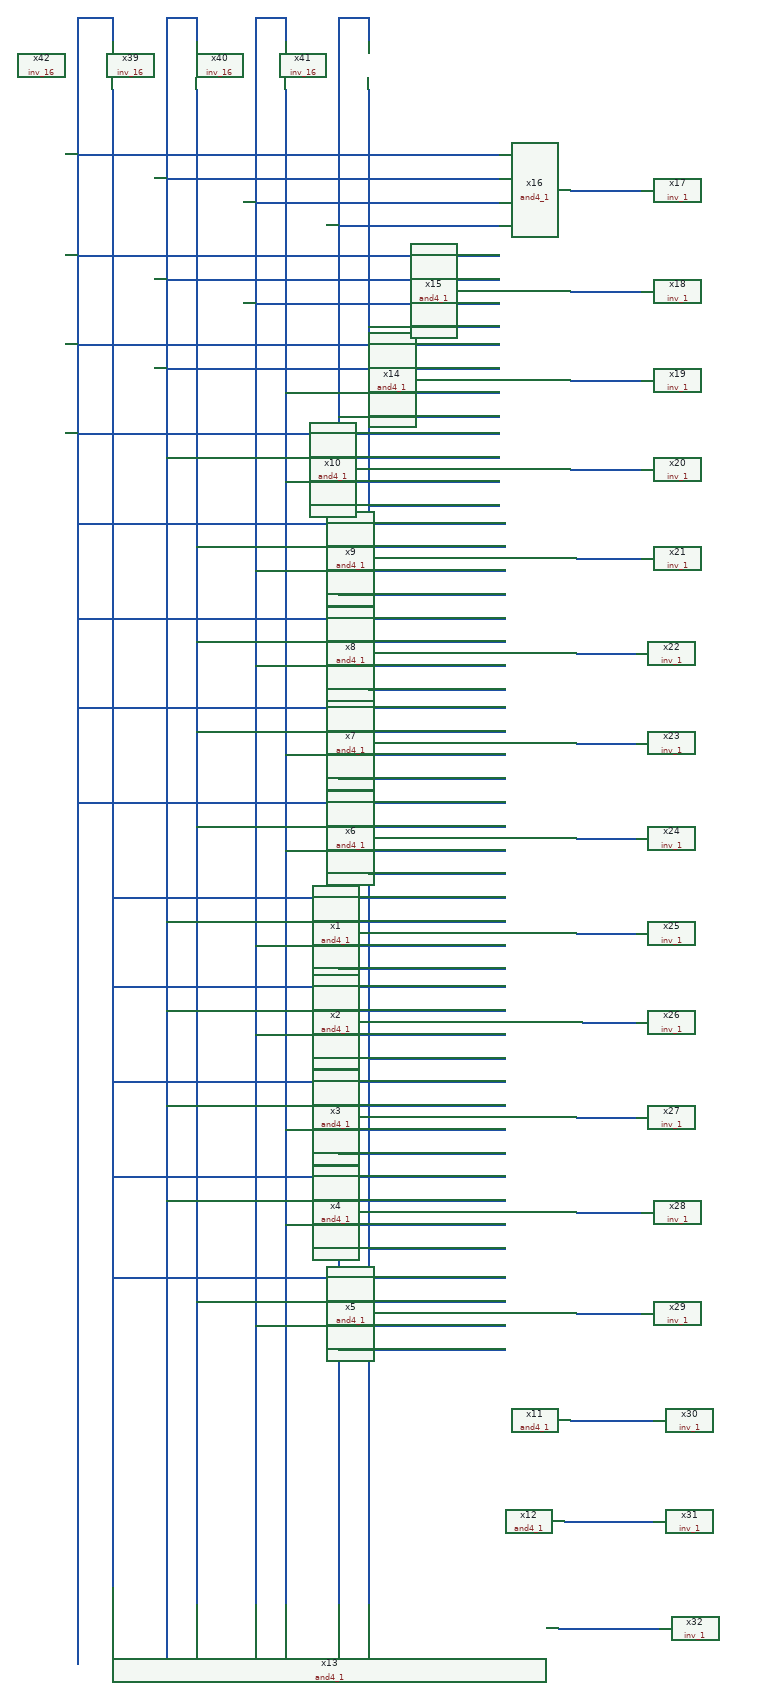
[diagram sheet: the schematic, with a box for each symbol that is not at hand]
v {xschem version=3.1.0 file_version=1.2
}
G {}
K {}
V {}
S {}
E {}
N 2040 -2550 2160 -2550 {
lab=#net1}
N 2040 -2380 2160 -2380 {
lab=#net2}
N 2040 -2230 2160 -2230 {
lab=#net3}
N 2040 -2080 2160 -2080 {
lab=#net4}
N 2050 -1930 2160 -1930 {
lab=#net5}
N 2050 -1770 2150 -1770 {
lab=#net6}
N 2050 -1620 2150 -1620 {
lab=#net7}
N 2050 -1460 2150 -1460 {
lab=#net8}
N 2050 -1300 2150 -1300 {
lab=#net9}
N 2060 -1150 2150 -1150 {
lab=#net10}
N 2050 -990 2150 -990 {
lab=#net11}
N 2050 -830 2160 -830 {
lab=#net12}
N 2050 -660 2160 -660 {
lab=#net13}
N 2040 -480 2180 -480 {
lab=#net14}
N 2030 -310 2180 -310 {
lab=#net15}
N 2020 -130 2190 -130 {
lab=#net16}
N 1270 -2840 1270 -2800 {
lab=#net17}
N 1210 -2840 1270 -2840 {
lab=#net17}
N 1410 -2840 1410 -2800 {
lab=#net18}
N 1360 -2840 1410 -2840 {
lab=#net18}
N 1560 -2840 1560 -2800 {
lab=#net19}
N 1510 -2840 1560 -2840 {
lab=#net19}
N 1700 -2840 1700 -2800 {
lab=#net20}
N 1650 -2840 1700 -2840 {
lab=#net20}
N 1210 -2610 1920 -2610 {
lab=#net17}
N 1210 -2840 1210 -2340 {
lab=#net17}
N 1210 -2340 1210 -1860 {
lab=#net17}
N 1210 -1860 1210 -1190 {
lab=#net17}
N 1210 -1190 1210 -70 {
lab=#net17}
N 1360 -2840 1360 -2390 {
lab=#net18}
N 1360 -2390 1360 -80 {
lab=#net18}
N 1510 -2840 1510 -2190 {
lab=#net19}
N 1650 -2840 1650 -2030 {
lab=#net20}
N 1270 -2720 1270 -2070 {
lab=#net27}
N 1410 -2720 1410 -2070 {
lab=#net28}
N 1560 -2720 1560 -2160 {
lab=#net29}
N 1700 -2720 1700 -2040 {
lab=#net30}
N 1360 -2570 1920 -2570 {
lab=#net18}
N 1510 -2530 1920 -2530 {
lab=#net19}
N 1650 -2490 1920 -2490 {
lab=#net20}
N 1210 -2440 1920 -2440 {
lab=#net17}
N 1360 -2400 1920 -2400 {
lab=#net18}
N 1510 -2360 1920 -2360 {
lab=#net19}
N 1700 -2320 1920 -2320 {
lab=#net30}
N 1210 -2290 1920 -2290 {
lab=#net17}
N 1360 -2250 1920 -2250 {
lab=#net18}
N 1510 -2190 1510 -2080 {
lab=#net19}
N 1270 -2070 1270 -1510 {
lab=#net27}
N 1410 -2070 1410 -1810 {
lab=#net28}
N 1510 -2080 1510 -1810 {
lab=#net19}
N 1560 -2160 1560 -1810 {
lab=#net29}
N 1650 -2030 1650 -1820 {
lab=#net20}
N 1700 -2040 1700 -1820 {
lab=#net30}
N 1650 -2170 1920 -2170 {
lab=#net20}
N 1560 -2210 1920 -2210 {
lab=#net29}
N 1210 -2140 1920 -2140 {
lab=#net17}
N 1360 -2100 1920 -2100 {
lab=#net18}
N 1560 -2060 1920 -2060 {
lab=#net29}
N 1700 -2020 1920 -2020 {
lab=#net30}
N 1210 -1990 1930 -1990 {
lab=#net17}
N 1410 -1950 1930 -1950 {
lab=#net28}
N 1510 -1910 1930 -1910 {
lab=#net19}
N 1650 -1870 1930 -1870 {
lab=#net20}
N 1410 -1810 1410 -1340 {
lab=#net28}
N 1510 -1810 1510 -1400 {
lab=#net19}
N 1560 -1810 1560 -1340 {
lab=#net29}
N 1650 -1820 1650 -1340 {
lab=#net20}
N 1700 -1820 1700 -1340 {
lab=#net30}
N 1210 -1830 1930 -1830 {
lab=#net17}
N 1410 -1790 1930 -1790 {
lab=#net28}
N 1510 -1750 1930 -1750 {
lab=#net19}
N 1700 -1710 1930 -1710 {
lab=#net30}
N 1210 -1680 1930 -1680 {
lab=#net17}
N 1410 -1640 1930 -1640 {
lab=#net28}
N 1560 -1600 1930 -1600 {
lab=#net29}
N 1650 -1560 1930 -1560 {
lab=#net20}
N 1210 -1520 1930 -1520 {
lab=#net17}
N 1410 -1480 1930 -1480 {
lab=#net28}
N 1560 -1440 1930 -1440 {
lab=#net29}
N 1700 -1400 1930 -1400 {
lab=#net30}
N 1270 -1510 1270 -990 {
lab=#net27}
N 1410 -1340 1410 -990 {
lab=#net28}
N 1510 -1400 1510 -990 {
lab=#net19}
N 1560 -1340 1560 -990 {
lab=#net29}
N 1650 -1340 1650 -980 {
lab=#net20}
N 1700 -1340 1700 -990 {
lab=#net30}
N 1270 -1360 1930 -1360 {
lab=#net27}
N 1360 -1320 1930 -1320 {
lab=#net18}
N 1510 -1280 1930 -1280 {
lab=#net19}
N 1650 -1240 1930 -1240 {}
N 1270 -1210 1930 -1210 {}
N 1360 -1170 1930 -1170 {}
N 1510 -1130 1930 -1130 {}
N 1700 -1090 1930 -1090 {}
N 1410 -990 1410 -580 {}
N 1270 -990 1270 -560 {}
N 1510 -990 1510 -560 {}
N 1560 -990 1560 -560 {}
N 1650 -980 1650 -570 {}
N 1700 -990 1700 -570 {}
N 1270 -1050 1930 -1050 {}
N 1270 -890 1930 -890 {}
N 1360 -1010 1930 -1010 {}
N 1560 -970 1930 -970 {}
N 1650 -930 1930 -930 {}
N 1700 -770 1930 -770 {}
N 1560 -810 1930 -810 {}
N 1360 -850 1930 -850 {}
N 1270 -720 1930 -720 {}
N 1410 -680 1930 -680 {}
N 1510 -640 1930 -640 {}
N 1650 -600 1930 -600 {}
N 1270 -560 1270 -200 {}
N 1410 -580 1410 -170 {}
N 1510 -560 1510 -170 {}
N 1560 -560 1560 -170 {}
N 1650 -570 1650 -170 {}
N 1700 -570 1700 -170 {}
C {sky130_stdcells/and4_1.sym} 1990 -1300 0 0 {name=x1 VGND=VGND VNB=VNB VPB=VPB VPWR=VPWR prefix=sky130_fd_sc_hd__ }
C {sky130_stdcells/and4_1.sym} 1990 -1150 0 0 {name=x2 VGND=VGND VNB=VNB VPB=VPB VPWR=VPWR prefix=sky130_fd_sc_hd__ }
C {sky130_stdcells/and4_1.sym} 1990 -990 0 0 {name=x3 VGND=VGND VNB=VNB VPB=VPB VPWR=VPWR prefix=sky130_fd_sc_hd__ }
C {sky130_stdcells/and4_1.sym} 1990 -830 0 0 {name=x4 VGND=VGND VNB=VNB VPB=VPB VPWR=VPWR prefix=sky130_fd_sc_hd__ }
C {sky130_stdcells/and4_1.sym} 1990 -660 0 0 {name=x5 VGND=VGND VNB=VNB VPB=VPB VPWR=VPWR prefix=sky130_fd_sc_hd__ }
C {sky130_stdcells/and4_1.sym} 1990 -1460 0 0 {name=x6 VGND=VGND VNB=VNB VPB=VPB VPWR=VPWR prefix=sky130_fd_sc_hd__ }
C {sky130_stdcells/and4_1.sym} 1990 -1620 0 0 {name=x7 VGND=VGND VNB=VNB VPB=VPB VPWR=VPWR prefix=sky130_fd_sc_hd__ }
C {sky130_stdcells/and4_1.sym} 1990 -1770 0 0 {name=x8 VGND=VGND VNB=VNB VPB=VPB VPWR=VPWR prefix=sky130_fd_sc_hd__ }
C {sky130_stdcells/and4_1.sym} 1990 -1930 0 0 {name=x9 VGND=VGND VNB=VNB VPB=VPB VPWR=VPWR prefix=sky130_fd_sc_hd__ }
C {sky130_stdcells/and4_1.sym} 1980 -2080 0 0 {name=x10 VGND=VGND VNB=VNB VPB=VPB VPWR=VPWR prefix=sky130_fd_sc_hd__ }
C {sky130_stdcells/and4_1.sym} 1980 -480 0 0 {name=x11 VGND=VGND VNB=VNB VPB=VPB VPWR=VPWR prefix=sky130_fd_sc_hd__ }
C {sky130_stdcells/and4_1.sym} 1970 -310 0 0 {name=x12 VGND=VGND VNB=VNB VPB=VPB VPWR=VPWR prefix=sky130_fd_sc_hd__ }
C {sky130_stdcells/and4_1.sym} 1960 -130 0 0 {name=x13 VGND=VGND VNB=VNB VPB=VPB VPWR=VPWR prefix=sky130_fd_sc_hd__ }
C {sky130_stdcells/and4_1.sym} 1980 -2230 0 0 {name=x14 VGND=VGND VNB=VNB VPB=VPB VPWR=VPWR prefix=sky130_fd_sc_hd__ }
C {sky130_stdcells/and4_1.sym} 1980 -2380 0 0 {name=x15 VGND=VGND VNB=VNB VPB=VPB VPWR=VPWR prefix=sky130_fd_sc_hd__ }
C {sky130_stdcells/and4_1.sym} 1980 -2550 0 0 {name=x16 VGND=VGND VNB=VNB VPB=VPB VPWR=VPWR prefix=sky130_fd_sc_hd__ }
C {sky130_stdcells/inv_1.sym} 2200 -2550 0 0 {name=x17 VGND=VGND VNB=VNB VPB=VPB VPWR=VPWR prefix=sky130_fd_sc_hd__ }
C {sky130_stdcells/inv_1.sym} 2200 -2380 0 0 {name=x18 VGND=VGND VNB=VNB VPB=VPB VPWR=VPWR prefix=sky130_fd_sc_hd__ }
C {sky130_stdcells/inv_1.sym} 2200 -2230 0 0 {name=x19 VGND=VGND VNB=VNB VPB=VPB VPWR=VPWR prefix=sky130_fd_sc_hd__ }
C {sky130_stdcells/inv_1.sym} 2200 -2080 0 0 {name=x20 VGND=VGND VNB=VNB VPB=VPB VPWR=VPWR prefix=sky130_fd_sc_hd__ }
C {sky130_stdcells/inv_1.sym} 2200 -1930 0 0 {name=x21 VGND=VGND VNB=VNB VPB=VPB VPWR=VPWR prefix=sky130_fd_sc_hd__ }
C {sky130_stdcells/inv_1.sym} 2190 -1770 0 0 {name=x22 VGND=VGND VNB=VNB VPB=VPB VPWR=VPWR prefix=sky130_fd_sc_hd__ }
C {sky130_stdcells/inv_1.sym} 2190 -1620 0 0 {name=x23 VGND=VGND VNB=VNB VPB=VPB VPWR=VPWR prefix=sky130_fd_sc_hd__ }
C {sky130_stdcells/inv_1.sym} 2190 -1460 0 0 {name=x24 VGND=VGND VNB=VNB VPB=VPB VPWR=VPWR prefix=sky130_fd_sc_hd__ }
C {sky130_stdcells/inv_1.sym} 2190 -1300 0 0 {name=x25 VGND=VGND VNB=VNB VPB=VPB VPWR=VPWR prefix=sky130_fd_sc_hd__ }
C {sky130_stdcells/inv_1.sym} 2190 -1150 0 0 {name=x26 VGND=VGND VNB=VNB VPB=VPB VPWR=VPWR prefix=sky130_fd_sc_hd__ }
C {sky130_stdcells/inv_1.sym} 2190 -990 0 0 {name=x27 VGND=VGND VNB=VNB VPB=VPB VPWR=VPWR prefix=sky130_fd_sc_hd__ }
C {sky130_stdcells/inv_1.sym} 2200 -830 0 0 {name=x28 VGND=VGND VNB=VNB VPB=VPB VPWR=VPWR prefix=sky130_fd_sc_hd__ }
C {sky130_stdcells/inv_1.sym} 2200 -660 0 0 {name=x29 VGND=VGND VNB=VNB VPB=VPB VPWR=VPWR prefix=sky130_fd_sc_hd__ }
C {sky130_stdcells/inv_1.sym} 2220 -480 0 0 {name=x30 VGND=VGND VNB=VNB VPB=VPB VPWR=VPWR prefix=sky130_fd_sc_hd__ }
C {sky130_stdcells/inv_1.sym} 2220 -310 0 0 {name=x31 VGND=VGND VNB=VNB VPB=VPB VPWR=VPWR prefix=sky130_fd_sc_hd__ }
C {sky130_stdcells/inv_16.sym} 1410 -2760 1 0 {name=x39 VGND=VGND VNB=VNB VPB=VPB VPWR=VPWR prefix=sky130_fd_sc_hd__ }
C {sky130_stdcells/inv_16.sym} 1560 -2760 1 0 {name=x40 VGND=VGND VNB=VNB VPB=VPB VPWR=VPWR prefix=sky130_fd_sc_hd__ }
C {sky130_stdcells/inv_16.sym} 1700 -2760 1 0 {name=x41 VGND=VGND VNB=VNB VPB=VPB VPWR=VPWR prefix=sky130_fd_sc_hd__ }
C {sky130_stdcells/inv_16.sym} 1270 -2760 1 0 {name=x42 VGND=VGND VNB=VNB VPB=VPB VPWR=VPWR prefix=sky130_fd_sc_hd__ }
C {sky130_stdcells/inv_1.sym} 2230 -130 0 0 {name=x32 VGND=VGND VNB=VNB VPB=VPB VPWR=VPWR prefix=sky130_fd_sc_hd__ }
